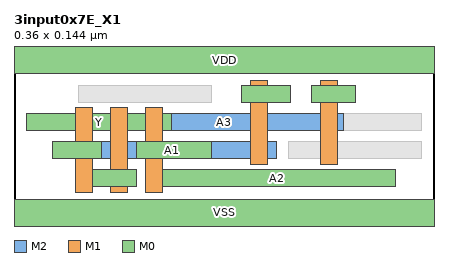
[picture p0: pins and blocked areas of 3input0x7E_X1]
MACRO 3input0x7E_X1
  CLASS CORE ;
  ORIGIN 0 0 ;
  FOREIGN 3input0x7E_X1 0 0 ;
  SIZE 0.3600 BY 0.1440 ;
  SYMMETRY X Y ;
  SITE coresite ;
  PIN A1
    DIRECTION INPUT ;
    USE SIGNAL ;
    PORT
      LAYER M2 ;
        RECT 0.0450 0.0530 0.2250 0.0670 ;
      LAYER M1 ;
        RECT 0.0525 0.0240 0.0675 0.0960 ;
        RECT 0.2025 0.0480 0.2175 0.1200 ;
      LAYER M0 ;
        RECT 0.1950 0.1010 0.2370 0.1150 ;
        RECT 0.0330 0.0530 0.0750 0.0670 ;
    END
  END A1
  PIN A2
    DIRECTION INPUT ;
    USE SIGNAL ;
    PORT
      LAYER M0 ;
        RECT 0.1230 0.0290 0.3270 0.0430 ;
    END
  END A2
  PIN A3
    DIRECTION INPUT ;
    USE SIGNAL ;
    PORT
      LAYER M2 ;
        RECT 0.0780 0.0770 0.2820 0.0910 ;
      LAYER M1 ;
        RECT 0.0825 0.0240 0.0975 0.0960 ;
        RECT 0.2625 0.0480 0.2775 0.1200 ;
      LAYER M0 ;
        RECT 0.2550 0.1010 0.2925 0.1150 ;
        RECT 0.0675 0.0290 0.1050 0.0430 ;
    END
  END A3
  PIN Y
    DIRECTION OUTPUT ;
    USE SIGNAL ;
    PORT
      LAYER M1 ;
        RECT 0.1125 0.0240 0.1275 0.0960 ;
      LAYER M0 ;
        RECT 0.0105 0.0770 0.1350 0.0910 ;
        RECT 0.1050 0.0530 0.1695 0.0670 ;
    END
  END Y
  PIN VDD
    DIRECTION INOUT ;
    USE POWER ;
    SHAPE ABUTMENT ;
    PORT
      LAYER M0 ;
        RECT 0.0000 0.1260 0.3600 0.1620 ;
    END
  END VDD
  PIN VSS
    DIRECTION INOUT ;
    USE GROUND ;
    SHAPE ABUTMENT ;
    PORT
      LAYER M0 ;
        RECT 0.0000 -0.0180 0.3600 0.0180 ;
    END
  END VSS
  OBS
    LAYER V1 ;
      RECT 0.0830 0.0770 0.0970 0.0910 ;
      RECT 0.2630 0.0770 0.2770 0.0910 ;
      RECT 0.0530 0.0530 0.0670 0.0670 ;
      RECT 0.2030 0.0530 0.2170 0.0670 ;
    LAYER V0 ;
      RECT 0.0830 0.0290 0.0970 0.0430 ;
      RECT 0.2630 0.1010 0.2770 0.1150 ;
      RECT 0.0530 0.0530 0.0670 0.0670 ;
      RECT 0.2030 0.1010 0.2170 0.1150 ;
      RECT 0.1130 0.0770 0.1270 0.0910 ;
      RECT 0.1130 0.0530 0.1270 0.0670 ;
    LAYER M0 ;
      RECT 0.2355 0.0530 0.3495 0.0670 ;
      RECT 0.1680 0.0770 0.3495 0.0910 ;
      RECT 0.0555 0.1010 0.1695 0.1150 ;
  END
END 3input0x7E_X1
